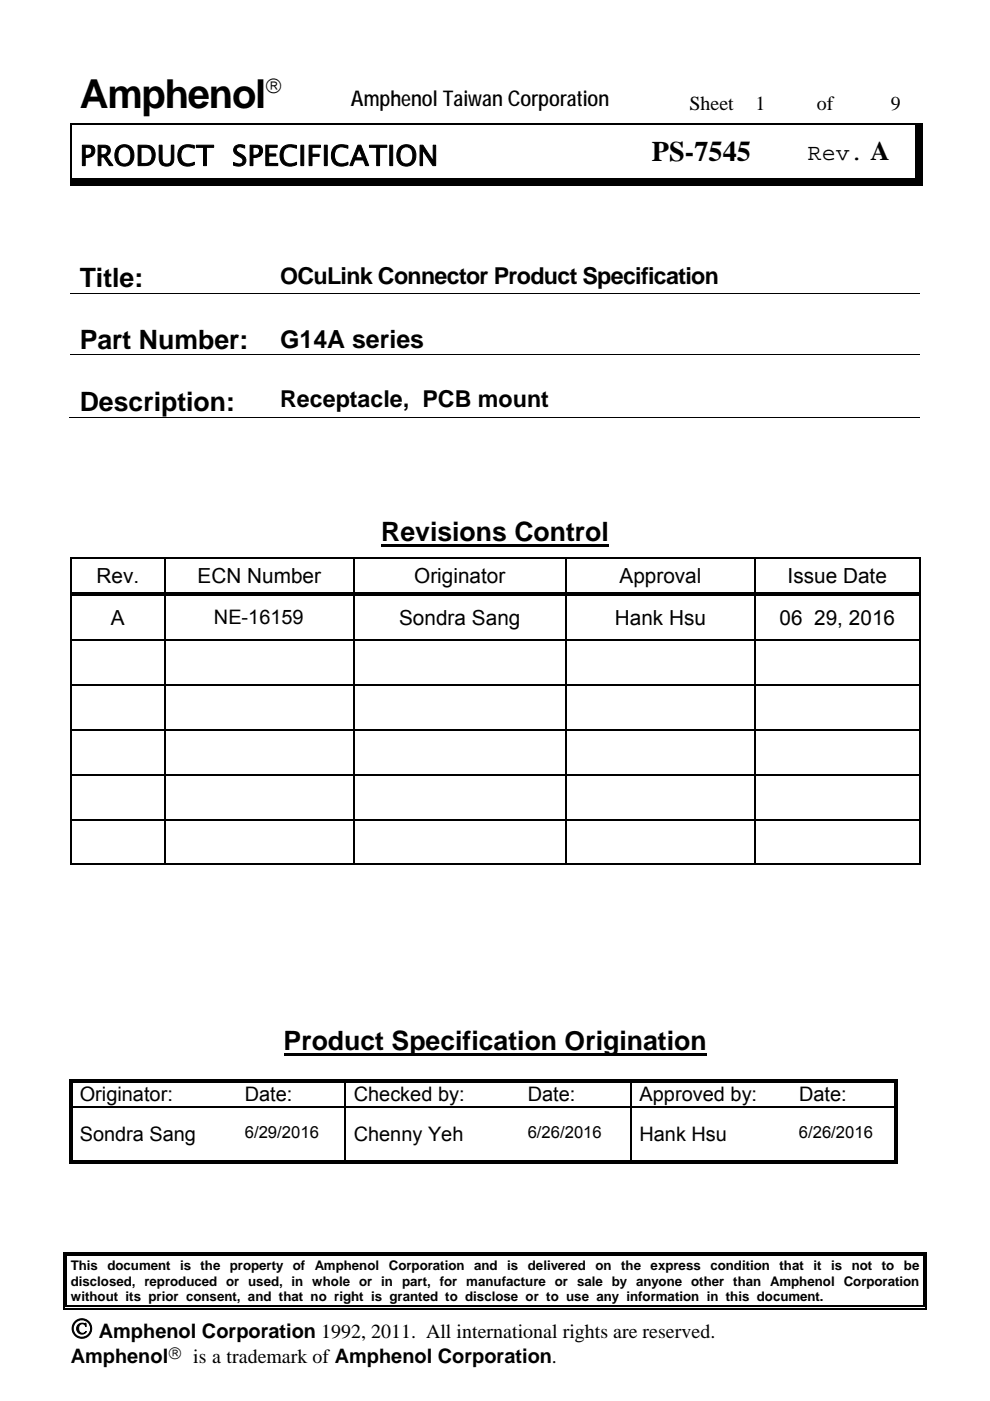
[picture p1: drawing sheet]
<svg xmlns="http://www.w3.org/2000/svg" width="210mm" height="297mm" viewBox="0 0 210 297" stroke-linecap="round" stroke-linejoin="round" font-family="sans-serif">
<defs><g id="words">
<text font-size="8.5" x="16.9" y="22.9">Amphenol</text>
<g font-size="6">
<text x="16.9" y="35.1">PRODUCT SPECIFICATION</text>
<text x="138.3" y="34.1">PS-7545</text>
<text x="15" y="283.7">©</text>
</g>
<g font-size="5.7">
<text x="184.6" y="33.8">A</text>
<text x="16.9" y="60.9">Title:</text>
<text x="16.9" y="73.9">Part Number:</text>
<text x="16.9" y="87.1">Description:</text>
<text x="80.9" y="114.8">Revisions Control</text>
<text x="60.2" y="222.7">Product Specification Origination</text>
</g>
<text font-size="5.3" x="59.4" y="73.7">G14A series</text>
<g font-size="4.9">
<text x="171.4" y="33.8">Rev.</text>
<text x="59.4" y="60.3">OCuLink Connector Product Specification</text>
<text x="59.4" y="86.4">Receptacle, PCB mount</text>
</g>
<g font-size="4.6">
<text x="56.2" y="19.8">®</text>
<text x="74.4" y="22.4">Amphenol Taiwan Corporation</text>
</g>
<g font-size="4.4">
<text x="20.5" y="123.5">Rev.</text>
<text x="41.9" y="123.5">ECN Number</text>
<text x="87.9" y="123.5">Originator</text>
<text x="131.4" y="123.5">Approval</text>
<text x="167" y="123.5">Issue Date</text>
<text x="23.5" y="132.5">A</text>
<text x="84.6" y="132.5">Sondra Sang</text>
<text x="130.4" y="132.5">Hank Hsu</text>
<text x="165.3" y="132.5">06 29, 2016</text>
</g>
<g font-size="4.2">
<text x="146.2" y="23.2">Sheet</text>
<text x="160.2" y="23.2">1</text>
<text x="173.3" y="23.2">of</text>
<text x="189" y="23.2">9</text>
<text x="45.4" y="132.4">NE-16159</text>
<text x="16.9" y="233.5">Originator:</text>
<text x="51.9" y="233.5">Date:</text>
<text x="75" y="233.5">Checked by:</text>
<text x="111.9" y="233.5">Date:</text>
<text x="135.7" y="233.5">Approved by:</text>
<text x="169.5" y="233.5">Date:</text>
<text x="16.9" y="241.9">Sondra Sang</text>
<text x="75" y="241.9">Chenny Yeh</text>
<text x="135.6" y="241.9">Hank Hsu</text>
<text x="21" y="283.7">Amphenol Corporation 1992, 2011. All international rights are reserved.</text>
<text x="15" y="289">Amphenol</text>
<text x="41" y="289">is a trademark of Amphenol Corporation.</text>
</g>
<text font-size="3.7" x="35.7" y="288.1">®</text>
<g font-size="3.5">
<text x="51.9" y="241.2">6/29/2016</text>
<text x="111.9" y="241.2">6/26/2016</text>
<text x="169.4" y="241.2">6/26/2016</text>
</g>
<g font-size="2.8">
<text x="15" y="269.2">This</text>
<text x="22.8" y="269.2">document</text>
<text x="38.2" y="269.2">is</text>
<text x="42.5" y="269.2">the</text>
<text x="48.7" y="269.2">property of</text>
<text x="66.8" y="269.2">Amphenol</text>
<text x="82.5" y="269.2">Corporation</text>
<text x="100.6" y="269.2">and</text>
<text x="107.6" y="269.2">is</text>
<text x="112" y="269.2">delivered</text>
<text x="126.3" y="269.2">on</text>
<text x="131.8" y="269.2">the</text>
<text x="138" y="269.2">express</text>
<text x="150.7" y="269.2">condition</text>
<text x="165.3" y="269.2">that</text>
<text x="172.5" y="269.2">it</text>
<text x="176.3" y="269.2">is</text>
<text x="180.7" y="269.2">not</text>
<text x="187.1" y="269.2">to</text>
<text x="191.7" y="269.2">be</text>
<text x="15" y="272.6">disclosed, reproduced or used, in whole or in part, for manufacture or sale by anyone other than Amphenol Corporation</text>
<text x="15" y="275.9">without its prior consent, and that no right is granted to disclose or to use any information in this document.</text>
</g>
</g></defs>
<g fill="#000">
<path d="M14.9 26.2h.2v.2h-.2zM14.9 37.8h117.6v1.5h-117.6zM132.3 37.8h1.6v1.5h-1.6zM133.9 37.8h31.1v1.5h-31.1zM164.8 37.8h29.4v1.5h-29.4zM194.2 26.2h1.6v.2h-1.6zM194.2 26.4h1.6v12.9h-1.6zM194.2 37.8h1.6v1.5h-1.6zM57.3 88.3h.1v.2h-.1zM14.9 118.1h.2v.3h-.2zM34.9 118.1h.2v.3h-.2zM74.9 118.1h.2v.3h-.2z"/>
<path d="M80.9 115.4h48.3v.6h-48.3zM119.9 118.1h.3v.3h-.3zM160 118.1h.3v.3h-.3zM194.9 118.1h.3v.3h-.3zM194.9 118.1h.3v.2h-.3zM14.9 125.5h.2v.8h-.2zM14.9 135.6h.2v.2h-.2zM34.9 126.3h.2zM34.9 125.5h.7v.3h-.7zM34.9 126h.7v.3h-.7zM34.9 135.6h.2v.2h-.2zM74.9 126.3h.2z"/>
<path d="M74.9 125.5h.7v.3h-.7zM74.9 126h.7v.3h-.7zM74.9 135.6h.2v.2h-.2zM119.9 126.3h.3zM119.9 125.5h.8v.3h-.8zM119.9 126h.8v.3h-.8zM119.9 135.6h.3v.2h-.3zM160 126.3h.3zM160 125.5h.8v.3h-.8zM160 126h.8v.3h-.8zM160 135.6h.3v.2h-.3zM194.9 125.5h.3v.8h-.3z"/>
<path d="M194.9 135.6h.3v.2h-.3zM14.9 145.1h.2v.3h-.2zM14.9 154.6h.2v.3h-.2zM34.9 145.1h.2v.3h-.2zM34.9 154.6h.2v.3h-.2zM74.9 145.1h.2v.3h-.2zM74.9 154.6h.2v.3h-.2zM119.9 145.1h.3v.3h-.3zM119.9 154.6h.3v.3h-.3zM160 145.1h.3v.3h-.3zM160 154.6h.3v.3h-.3zM194.9 145.1h.3v.3h-.3z"/>
<path d="M194.9 154.6h.3v.3h-.3zM14.9 164.1h.2v.3h-.2zM14.9 173.7h.2v.2h-.2zM34.9 164.1h.2v.3h-.2zM34.9 173.7h.2v.2h-.2zM74.9 164.1h.2v.3h-.2zM74.9 173.7h.2v.2h-.2zM119.9 164.1h.3v.3h-.3zM119.9 173.7h.3v.2h-.3zM160 164.1h.3v.3h-.3zM160 173.7h.3v.2h-.3zM194.9 164.1h.3v.3h-.3z"/>
<path d="M194.9 173.7h.3v.2h-.3zM194.9 183h.3v.3h-.3zM14.6 228.8h.3v.8h-.3zM14.6 228.8h.8v.2h-.8zM14.6 234.5h.3v.3h-.3zM15.1 229.3h.3v.3h-.3zM15.1 234.5h.3v.3h-.3zM50 228.8h.8v.2h-.8zM50 229.3h.8v.3h-.8zM60.2 223.3h89.7v.6h-89.7zM73 229.6h.3zM73 228.8h.8v.2h-.8z"/>
<path d="M73 229.3h.8v.3h-.8zM73 234.5h.3v.3h-.3zM110 228.8h.8v.2h-.8zM110 229.3h.8v.3h-.8zM133.6 229.6h.3zM133.6 228.8h.8v.2h-.8zM133.6 229.3h.8v.3h-.8zM133.6 234.5h.3v.3h-.3zM167.5 228.8h.8v.2h-.8zM167.5 229.3h.8v.3h-.8zM189.7 228.8h.7v.2h-.7zM189.7 229.3h.2v.3h-.2z"/>
<path d="M189.7 234.5h.2v.3h-.2zM190.2 228.8h.2v.8h-.2zM190.2 234.5h.2v.3h-.2zM14.6 246.5h.8v.3h-.8zM15.1 246h.3v.3h-.3zM49.8 246h.7v.3h-.7zM73 246h.8v.3h-.8zM109.8 246h.7v.3h-.7zM133.6 246h.8v.3h-.8zM133.6 246.5h.8v.3h-.8zM167.3 246h.7v.3h-.7zM189.7 246.5h.7v.3h-.7z"/>
<path d="M189.7 246h.2v.3h-.2zM190.2 246h.2v.8h-.2zM13.4 265.5h.2v.7h-.2zM13.4 265.5h.7v.2h-.7zM13.4 276.9h.2v.7h-.2zM13.4 277.4h.7v.2h-.7zM13.9 266h.2v.2h-.2zM13.9 276.9h.2v.2h-.2zM195.9 265.5h.7v.2h-.7zM195.9 266h.2v.2h-.2zM195.9 277.4h.7v.2h-.7zM195.9 276.9h.2v.2h-.2z"/>
<path d="M196.4 265.5h.2v.7h-.2zM196.4 276.9h.2v.7h-.2z"/>
</g>
<g fill="none" stroke="#000" stroke-width=".25">
<path d="M14.9 26.3h179.3M15 26.4v11.4M14.9 118.2h20M15 118.4v7.1M35 118.4v7.1M35.1 118.2h39.8M75 118.4v7.1M75.1 118.2h44.8M120 118.4v7.1M120.2 118.2h39.8M160.1 118.4v7.1M160.3 118.2h34.6"/>
<path d="M195 118.4v7.1M15 126.3v9.3M15 135.8v9.3M15.1 125.6h19.8M15.1 126.1h19.8M15.1 135.7h19.8M35 126.3v9.3M35 135.8v9.3M35.1 135.7h39.8M35.6 125.6h39.3M35.6 126.1h39.3M75 126.3v9.3"/>
<path d="M75 135.8v9.3M75.1 135.7h44.8M75.6 125.6h44.3M75.6 126.1h44.3M120 126.3v9.3M120 135.8v9.3M120.2 135.7h39.8M120.7 125.6h39.3M120.7 126.1h39.3M160.1 126.3v9.3M160.1 135.8v9.3M160.3 135.7h34.6"/>
<path d="M160.8 125.6h34.1M160.8 126.1h34.1M195 126.3v9.3M195 135.8v9.3M15 145.4v9.2M15 154.9v9.2M15.1 145.2h19.8M15.1 154.7h19.8M35 145.4v9.2M35 154.9v9.2M35.1 145.2h39.8M35.1 154.7h39.8"/>
<path d="M75 145.4v9.2M75 154.9v9.2M75.1 145.2h44.8M75.1 154.7h44.8M120 145.4v9.2M120 154.9v9.2M120.2 145.2h39.8M120.2 154.7h39.8M160.1 145.4v9.2M160.1 154.9v9.2M160.3 145.2h34.6M160.3 154.7h34.6"/>
<path d="M195 145.4v9.2M195 154.9v9.2M15 164.4v9.3M15 173.9v9.4M15.1 164.3h19.8M15.1 173.8h19.8M35 164.4v9.3M35 173.9v9.4M35.1 164.3h39.8M35.1 173.8h39.8M75 164.4v9.3M75 173.9v9.4"/>
<path d="M75.1 164.3h44.8M75.1 173.8h44.8M120 164.4v9.3M120 173.9v9.4M120.2 164.3h39.8M120.2 173.8h39.8M160.1 164.4v9.3M160.1 173.9v9.4M160.3 164.3h34.6M160.3 173.8h34.6M195 164.4v9.3M195 173.9v9.4"/>
<path d="M14.9 183.2h20M35.1 183.2h39.8M75.1 183.2h44.8M120.2 183.2h39.8M160.3 183.2h34.6M14.8 229.6v4.9M14.8 234.8v12M15.3 229.6v4.9M15.3 234.8v11.2M15.4 228.9h34.6M15.4 229.4h34.6M15.4 234.6h57.6"/>
<path d="M50.8 228.9h22.2M50.8 229.4h22.2M73.1 229.6v4.9M73.1 234.8v11.2M73.3 234.6h60.3M73.8 228.9h36.2M73.8 229.4h36.2M110.8 228.9h22.8M110.8 229.4h22.8M133.7 229.6v4.9M133.7 234.8v11.2M133.9 234.6h55.8"/>
<path d="M134.4 228.9h33.1M134.4 229.4h33.1M168.3 228.9h21.4M168.3 229.4h21.4M189.8 229.6v4.9M189.8 234.8v11.2M190.3 229.6v4.9M190.3 234.8v11.2M15.4 246.7h118.2M15.4 246.2h34.6M50.5 246.2h22.5M73.8 246.2h36.2"/>
<path d="M110.5 246.2h23.1M134.4 246.7h55.3M134.4 246.2h33.1M168 246.2h21.7M13.5 266.2v10.7M14 266.2v10.7M14.1 265.6h181.8M14.1 266.1h181.8M14.1 277.5h181.8M14.1 277h181.8M196 266.2v10.7M196.5 266.2v10.7"/>
</g>
<path d="M15 75.2h180M195 62.2h-180M14.8 88.4h180.2" fill="none" stroke="#000" stroke-width=".21"/>
<use href="#words"/>
</svg>
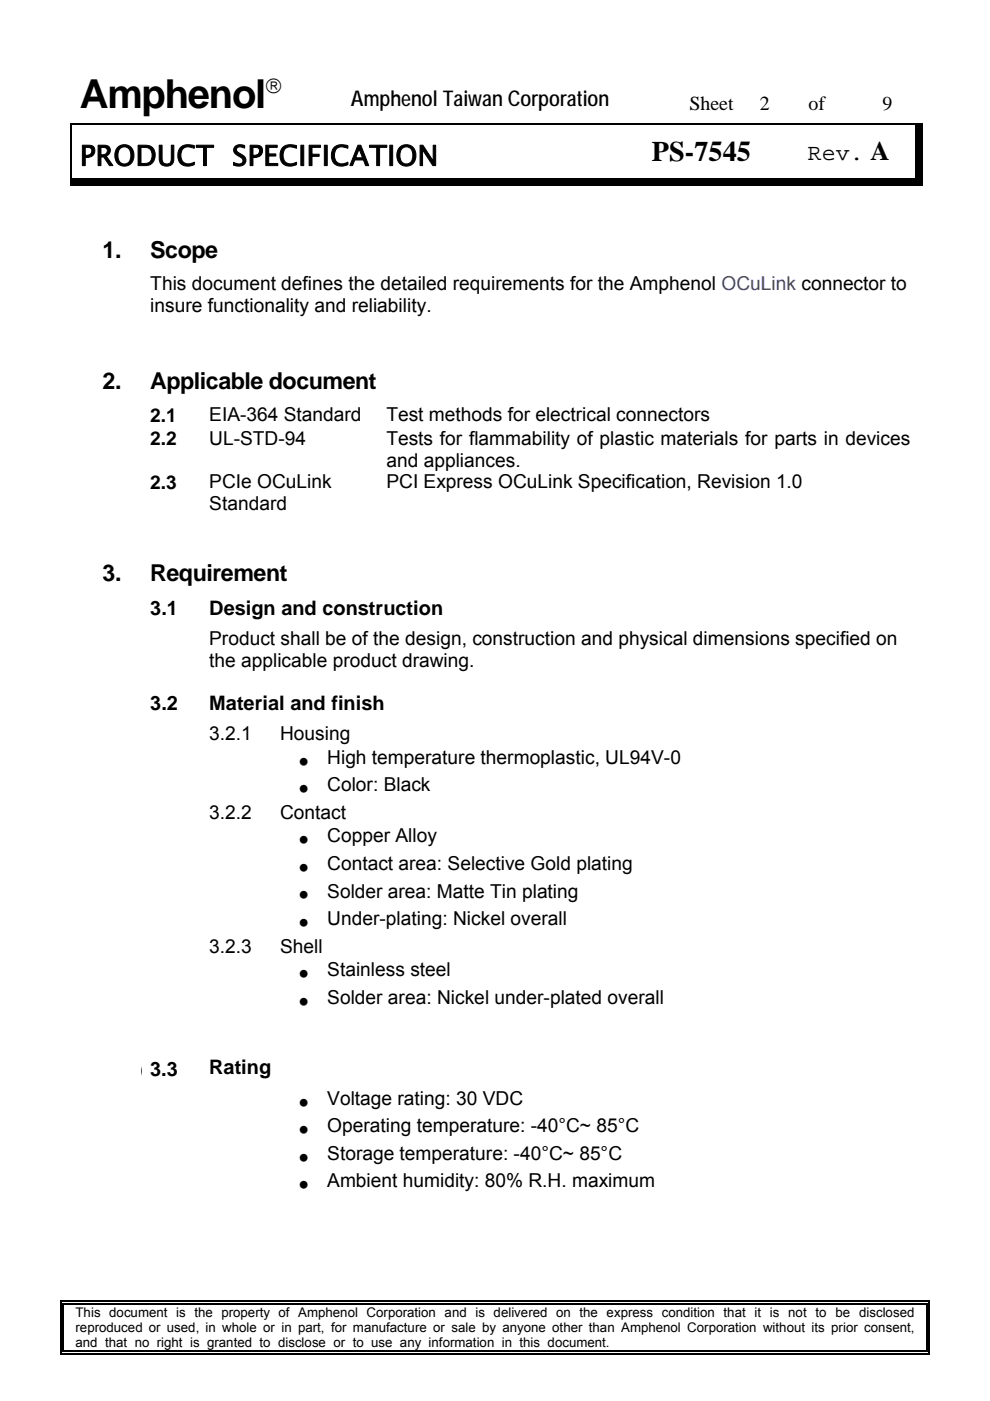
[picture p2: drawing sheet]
<svg xmlns="http://www.w3.org/2000/svg" width="210mm" height="297mm" viewBox="0 0 210 297" stroke-linecap="round" stroke-linejoin="round" font-family="sans-serif">
<defs><g id="words">
<text font-size="8.5" x="16.9" y="22.9">Amphenol</text>
<g font-size="6">
<text x="16.9" y="35.1">PRODUCT SPECIFICATION</text>
<text x="138.3" y="34.1">PS-7545</text>
</g>
<text font-size="5.7" x="184.6" y="33.8">A</text>
<g font-size="4.9">
<text x="171.4" y="33.8">Rev.</text>
<text x="21.8" y="54.6">1.</text>
<text x="31.9" y="54.6">Scope</text>
<text x="21.8" y="82.4">2.</text>
<text x="31.9" y="82.4">Applicable document</text>
<text x="21.8" y="123.1">3.</text>
<text x="31.9" y="123.1">Requirement</text>
</g>
<g font-size="4.6">
<text x="56.2" y="19.8">®</text>
<text x="74.4" y="22.4">Amphenol Taiwan Corporation</text>
<text x="63.4" y="162.8">•</text>
<text x="63.4" y="168.6">•</text>
<text x="63.4" y="179.5">•</text>
<text x="63.4" y="185.3">•</text>
<text x="63.4" y="191.1">•</text>
<text x="63.4" y="197">•</text>
<text x="63.4" y="207.8">•</text>
<text x="63.4" y="213.7">•</text>
<text x="63.4" y="235">•</text>
<text x="63.4" y="240.9">•</text>
<text x="63.4" y="246.7">•</text>
<text x="63.4" y="252.6">•</text>
</g>
<g font-size="4.2">
<text x="146.2" y="23.2">Sheet</text>
<text x="161.2" y="23.2">2</text>
<text x="171.5" y="23.2">of</text>
<text x="187.2" y="23.2">9</text>
<text x="31.9" y="130.3">3.1</text>
<text x="44.4" y="130.3">Design and construction</text>
<text x="31.9" y="150.5">3.2</text>
<text x="44.4" y="150.5">Material and finish</text>
<text x="44.4" y="227.7">Rating</text>
</g>
<g font-size="4.1">
<text x="31.9" y="61.6">This document defines the detailed requirements for the Amphenol OCuLink connector to</text>
<text x="31.9" y="66.2">insure functionality and reliability.</text>
<text x="31.9" y="89.5">2.1</text>
<text x="44.4" y="89.3">EIA-364 Standard</text>
<text x="81.9" y="89.3">Test methods for electrical connectors</text>
<text x="31.9" y="94.4">2.2</text>
<text x="44.4" y="94.3">UL-STD-94</text>
<text x="81.9" y="94.3">Tests for flammability of plastic materials for parts in devices</text>
<text x="82" y="98.9">and appliances.</text>
<text x="31.9" y="103.7">2.3</text>
<text x="44.4" y="103.6">PCIe OCuLink</text>
<text x="82" y="103.6">PCI Express OCuLink Specification, Revision 1.0</text>
<text x="44.4" y="108.2">Standard</text>
<text x="44.4" y="136.8">Product shall be of the design, construction and physical dimensions specified on</text>
<text x="44.4" y="141.4">the applicable product drawing.</text>
<text x="44.4" y="156.9">3.2.1</text>
<text x="59.4" y="156.9">Housing</text>
<text x="69.4" y="161.9">High temperature thermoplastic, UL94V-0</text>
<text x="69.4" y="167.8">Color: Black</text>
<text x="44.4" y="173.6">3.2.2</text>
<text x="59.4" y="173.6">Contact</text>
<text x="69.4" y="178.6">Copper Alloy</text>
<text x="69.4" y="184.4">Contact area: Selective Gold plating</text>
<text x="69.4" y="190.3">Solder area: Matte Tin plating</text>
<text x="69.4" y="196.1">Under-plating: Nickel overall</text>
<text x="44.4" y="202">3.2.3</text>
<text x="59.4" y="202">Shell</text>
<text x="69.4" y="207">Stainless steel</text>
<text x="69.4" y="212.8">Solder area: Nickel under-plated overall</text>
<text x="28.9" y="228.1">) 3.3</text>
<text x="69.4" y="234.2">Voltage rating: 30 VDC</text>
<text x="69.4" y="240">Operating temperature: -40°C~ 85°C</text>
<text x="69.4" y="245.9">Storage temperature: -40°C~ 85°C</text>
<text x="69.4" y="251.7">Ambient humidity: 80% R.H. maximum</text>
</g>
<g font-size="2.8">
<text x="16" y="279.2">This document is the property of Amphenol Corporation and is delivered on the express condition that it is not to be disclosed</text>
<text x="16" y="282.4">reproduced or used, in whole or in part, for manufacture or sale by anyone other than Amphenol Corporation without its prior consent,</text>
<text x="16" y="285.7">and that no right is granted to disclose or to use any information in this document.</text>
</g>
</g></defs>
<g fill="#000">
<path d="M14.9 26.2h.2v.2h-.2zM14.9 37.8h117.6v1.5h-117.6zM132.3 37.8h1.6v1.5h-1.6zM133.9 37.8h31.1v1.5h-31.1zM164.8 37.8h29.4v1.5h-29.4zM194.2 26.2h1.6v.2h-1.6zM194.2 26.4h1.6v12.9h-1.6zM194.2 37.8h1.6v1.5h-1.6zM12.7 275.8h.3v.8h-.3zM12.7 275.8h.8v.2h-.8zM13.2 276.3h.3v.3h-.3zM13.2 276.3h.3v.2h-.3z"/>
<path d="M13.5 275.8h.7v.2h-.7zM13.5 276.3h.7v.2h-.7zM105 275.8h.8v.2h-.8zM105 276.3h.8v.2h-.8zM196.5 275.8h.8v.2h-.8zM196.5 276.3h.3v.3h-.3zM196.5 276.3h.3v.2h-.3zM197 275.8h.3v.8h-.3zM12.7 286.9h.8v.2h-.8zM13.2 286.3h.3v.3h-.3zM196.5 286.9h.8v.2h-.8zM196.5 286.3h.3v.3h-.3z"/>
<path d="M197 286.3h.3v.8h-.3z"/>
</g>
<path d="M14.9 26.3h179.3M15 26.4v11.4M12.8 276.6v10.5M13.4 276.6v9.7M14.2 275.9h90.8M14.2 276.4h90.8M105.8 275.9h90.7M105.8 276.4h90.7M196.6 276.6v9.7M197.1 276.6v9.7M13.5 287h183M13.5 286.5h183" fill="none" stroke="#000" stroke-width=".25"/>
<use href="#words"/>
</svg>
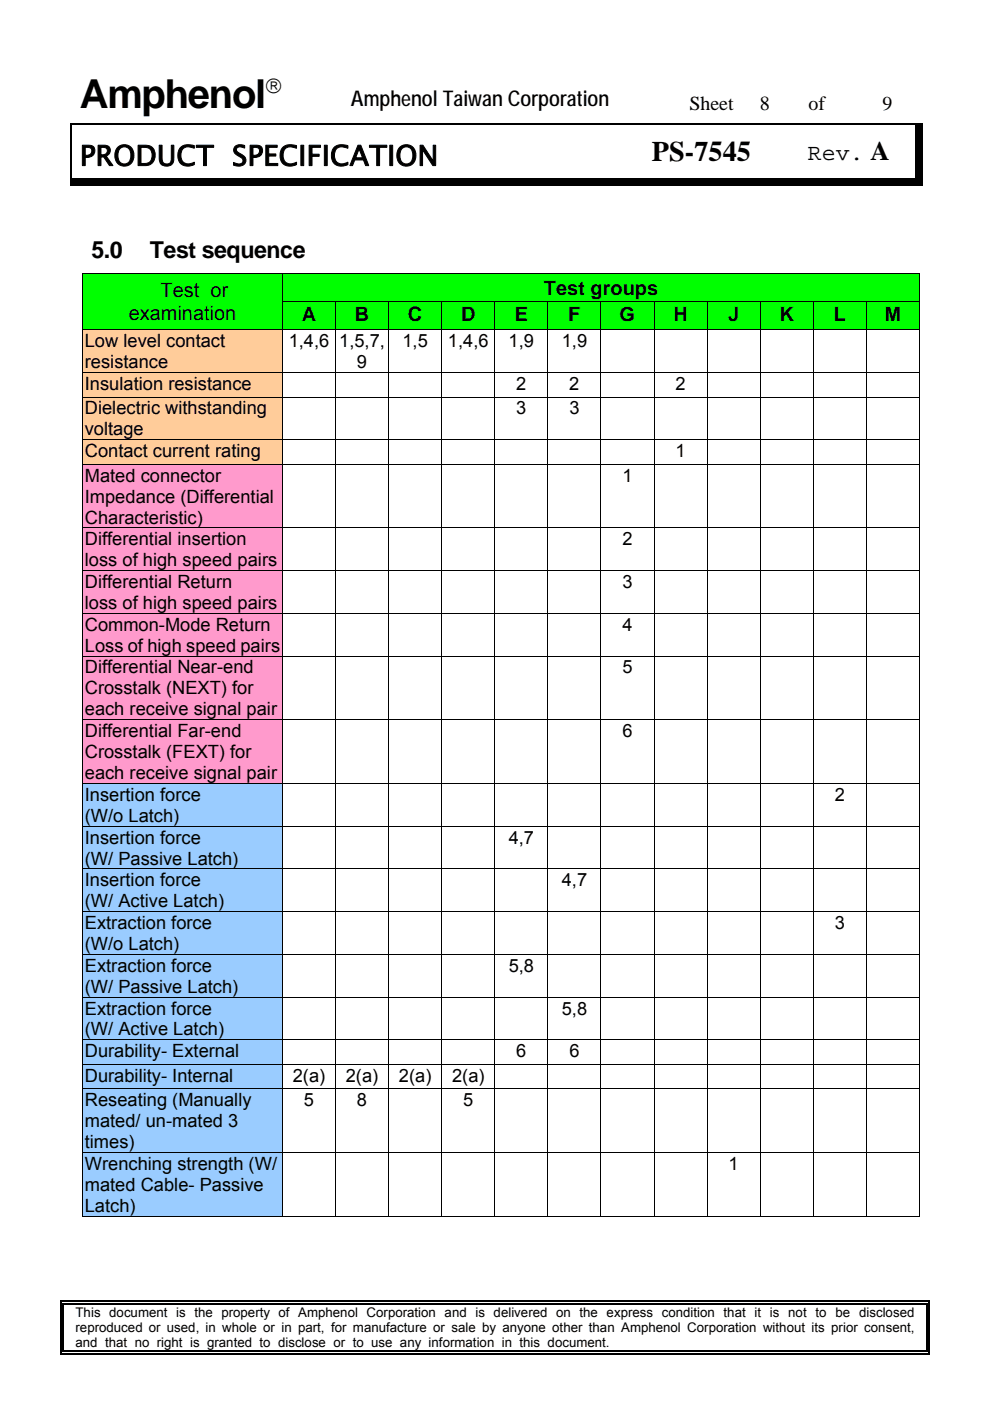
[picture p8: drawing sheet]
<svg xmlns="http://www.w3.org/2000/svg" width="210mm" height="297mm" viewBox="0 0 210 297" stroke-linecap="round" stroke-linejoin="round" font-family="sans-serif">
<defs><g id="words">
<text font-size="8.5" x="16.9" y="22.9">Amphenol</text>
<g font-size="6">
<text x="16.9" y="35.1">PRODUCT SPECIFICATION</text>
<text x="138.3" y="34.1">PS-7545</text>
</g>
<text font-size="5.7" x="184.6" y="33.8">A</text>
<g font-size="4.9">
<text x="171.4" y="33.8">Rev.</text>
<text x="19.4" y="54.7">5.0</text>
<text x="31.8" y="54.7">Test sequence</text>
</g>
<g font-size="4.6">
<text x="56.2" y="19.8">®</text>
<text x="74.4" y="22.4">Amphenol Taiwan Corporation</text>
</g>
<g font-size="4.2">
<text x="146.2" y="23.2">Sheet</text>
<text x="161.2" y="23.2">8</text>
<text x="171.5" y="23.2">of</text>
<text x="187.2" y="23.2">9</text>
<text x="34.1" y="63">Test or</text>
<text x="115.4" y="62.5">Test groups</text>
<text x="27.3" y="67.9">examination</text>
<text x="64" y="68.1">A</text>
<text x="75.3" y="68.1">B</text>
<text x="86.5" y="68.1">C</text>
<text x="97.8" y="68.1">D</text>
<text x="109.2" y="68.1">E</text>
<text x="120.5" y="68.1">F</text>
<text x="131.4" y="68.1">G</text>
<text x="142.8" y="68.1">H</text>
<text x="154.5" y="68.1">J</text>
<text x="165.3" y="68.1">K</text>
<text x="176.8" y="68.1">L</text>
<text x="187.6" y="68.1">M</text>
</g>
<g font-size="3.9">
<text x="18" y="73.6">Low level contact</text>
<text x="61.2" y="73.6">1,4,6 1,5,7,</text>
<text x="85.4" y="73.6">1,5</text>
<text x="95" y="73.6">1,4,6</text>
<text x="107.9" y="73.6">1,9</text>
<text x="119.1" y="73.6">1,9</text>
<text x="18" y="78.1">resistance</text>
<text x="18" y="82.7">Insulation resistance</text>
<text x="75.7" y="78.1">9</text>
<text x="109.5" y="82.7">2</text>
<text x="120.7" y="82.7">2</text>
<text x="143.3" y="82.7">2</text>
<text x="18" y="87.9">Dielectric withstanding</text>
<text x="109.5" y="87.9">3</text>
<text x="120.8" y="87.9">3</text>
<text x="18" y="92.3">voltage</text>
<text x="18" y="96.9">Contact current rating</text>
<text x="143.3" y="96.9">1</text>
<text x="18" y="102.1">Mated connector</text>
<text x="18" y="106.6">Impedance (Differential</text>
<text x="132" y="102.1">1</text>
<text x="18" y="111">Characteristic)</text>
<text x="18" y="115.6">Differential insertion</text>
<text x="132" y="115.6">2</text>
<text x="18" y="120.1">loss of high speed pairs</text>
<text x="18" y="124.7">Differential Return</text>
<text x="132" y="124.7">3</text>
<text x="18" y="129.1">loss of high speed pairs</text>
<text x="18" y="133.7">Common-Mode Return</text>
<text x="132" y="133.7">4</text>
<text x="18" y="138.2">Loss of high speed pairs</text>
<text x="18" y="142.8">Differential Near-end</text>
<text x="132" y="142.8">5</text>
<text x="18" y="147.2">Crosstalk (NEXT) for</text>
<text x="18" y="151.7">each receive signal pair</text>
<text x="18" y="156.3">Differential Far-end</text>
<text x="18" y="160.7">Crosstalk (FEXT) for</text>
<text x="132" y="156.3">6</text>
<text x="18" y="165.2">each receive signal pair</text>
<text x="18" y="169.8">Insertion force</text>
<text x="177" y="169.8">2</text>
<text x="18" y="174.2">(W/o Latch)</text>
<text x="18" y="178.9">Insertion force</text>
<text x="107.9" y="178.9">4,7</text>
<text x="18" y="183.3">(W/ Passive Latch)</text>
<text x="18" y="187.9">Insertion force</text>
<text x="119.2" y="187.9">4,7</text>
<text x="18" y="192.4">(W/ Active Latch)</text>
<text x="18" y="197">Extraction force</text>
<text x="177" y="197">3</text>
<text x="18" y="201.4">(W/o Latch)</text>
<text x="18" y="206">Extraction force</text>
<text x="107.9" y="206">5,8</text>
<text x="18" y="210.5">(W/ Passive Latch)</text>
<text x="18" y="215.1">Extraction force</text>
<text x="119.2" y="215.1">5,8</text>
<text x="18" y="219.5">(W/ Active Latch)</text>
<text x="18" y="224.2">Durability- External</text>
<text x="109.5" y="224.2">6</text>
<text x="120.8" y="224.2">6</text>
<text x="18" y="229.3">Durability- Internal</text>
<text x="62.1" y="229.3">2(a)</text>
<text x="73.3" y="229.3">2(a)</text>
<text x="84.6" y="229.3">2(a)</text>
<text x="95.9" y="229.3">2(a)</text>
<text x="18" y="234.5">Reseating (Manually</text>
<text x="18" y="239">mated/ un-mated 3</text>
<text x="64.5" y="234.5">5</text>
<text x="75.7" y="234.5">8</text>
<text x="98.3" y="234.5">5</text>
<text x="18" y="243.4">times)</text>
<text x="18" y="248">Wrenching strength (W/</text>
<text x="154.5" y="248">1</text>
<text x="18" y="252.5">mated Cable- Passive</text>
<text x="18" y="256.9">Latch)</text>
</g>
<g font-size="2.8">
<text x="16" y="279.2">This document is the property of Amphenol Corporation and is delivered on the express condition that it is not to be disclosed</text>
<text x="16" y="282.4">reproduced or used, in whole or in part, for manufacture or sale by anyone other than Amphenol Corporation without its prior consent,</text>
<text x="16" y="285.7">and that no right is granted to disclose or to use any information in this document.</text>
</g>
</g></defs>
<g fill="#000">
<path d="M14.9 26.2h.2v.2h-.2zM14.9 37.8h117.6v1.5h-117.6zM132.3 37.8h1.6v1.5h-1.6zM133.9 37.8h31.1v1.5h-31.1zM164.8 37.8h29.4v1.5h-29.4zM194.2 26.2h1.6v.2h-1.6zM194.2 26.4h1.6v12.9h-1.6zM194.2 37.8h1.6v1.5h-1.6zM12.7 275.8h.3v.8h-.3zM12.7 275.8h.8v.2h-.8zM13.2 276.3h.3v.3h-.3zM13.2 276.3h.3v.2h-.3z"/>
<path d="M13.5 275.8h.7v.2h-.7zM13.5 276.3h.7v.2h-.7zM105 275.8h.8v.2h-.8zM105 276.3h.8v.2h-.8zM196.5 275.8h.8v.2h-.8zM196.5 276.3h.3v.3h-.3zM196.5 276.3h.3v.2h-.3zM197 275.8h.3v.8h-.3zM12.7 286.9h.8v.2h-.8zM13.2 286.3h.3v.3h-.3zM196.5 286.9h.8v.2h-.8zM196.5 286.3h.3v.3h-.3z"/>
<path d="M197 286.3h.3v.8h-.3z"/>
</g>
<path d="M14.9 26.3h179.3M15 26.4v11.4M12.8 276.6v10.5M13.4 276.6v9.7M14.2 275.9h90.8M14.2 276.4h90.8M105.8 275.9h90.7M105.8 276.4h90.7M196.6 276.6v9.7M197.1 276.6v9.7M13.5 287h183M13.5 286.5h183" fill="none" stroke="#000" stroke-width=".25"/>
<g fill="#0f0">
<path d="M17.6 58h42.2v11.8h-42.2z"/>
<path d="M18 59.1h41.4v4.8h-41.4z"/>
<path d="M18 63.9h41.4v4.9h-41.4z"/>
<path d="M59.9 58h135v5.9h-135z"/>
<path d="M60.4 58.5h134.1v4.9h-134.1z"/>
</g>
<path d="M17.4 57.9h.2v.1h-.2zM194.9 57.9h.2v.1h-.2z" fill="#000"/>
<path d="M17.5 58v5.9M59.9 58v5.9M194.9 58h-177.5M195 58v5.9" fill="none" stroke="#000" stroke-width=".21"/>
<g fill="#0f0">
<path d="M59.9 64h11.2v5.8h-11.2z"/>
<path d="M60.4 64h10.3v5h-10.3z"/>
<path d="M71.2 64h11.2v5.8h-11.2z"/>
<path d="M71.7 64h10.2v5h-10.2z"/>
<path d="M82.4 64h11.2v5.8h-11.2z"/>
<path d="M82.9 64h10.3v5h-10.3z"/>
<path d="M93.7 64h11.2v5.8h-11.2z"/>
<path d="M94.2 64h10.3v5h-10.3z"/>
<path d="M105 64h11.1v5.8h-11.1z"/>
<path d="M105.5 64h10.2v5h-10.2z"/>
<path d="M116.2 64h11.2v5.8h-11.2z"/>
<path d="M116.7 64h10.3v5h-10.3z"/>
<path d="M127.5 64h11.1v5.8h-11.1z"/>
<path d="M128 64h10.2v5h-10.2z"/>
<path d="M138.7 64h11.2v5.8h-11.2z"/>
<path d="M139.2 64h10.3v5h-10.3z"/>
<path d="M150 64h11.2v5.8h-11.2z"/>
<path d="M150.5 64h10.3v5h-10.3z"/>
<path d="M161.3 64h11.1v5.8h-11.1z"/>
<path d="M161.7 64h10.3v5h-10.3z"/>
<path d="M172.6 64h11.1v5.8h-11.1z"/>
<path d="M173 64h10.3v5h-10.3z"/>
<path d="M183.9 64h11v5.8h-11z"/>
<path d="M184.3 64h10.2v5h-10.2z"/>
</g>
<path d="M17.4 63.9h.2v.1h-.2z" fill="#000"/>
<g fill="none" stroke="#000" stroke-width=".21">
<path d="M17.5 64v5.8M59.9 63.9h135.2M59.9 64v5.8M71.2 64v5.8M82.4 64v5.8M93.7 64v5.8M105 64v5.8M116.2 64v5.8M127.5 64v5.8M138.7 64v5.8M150 64v5.8M161.2 64v5.8"/>
<path d="M172.5 64v5.8M183.8 64v5.8M195 64v5.8"/>
</g>
<g fill="#ffcc9a">
<path d="M17.6 70h42.2v8.9h-42.2z"/>
<path d="M18 70h41.4v4.5h-41.4z"/>
<path d="M18 74.5h41.4v4.4h-41.4z"/>
</g>
<g fill="none" stroke="#000" stroke-width=".21">
<path d="M17.4 69.9h177.7M17.5 70v8.9M59.9 70v8.9M71.2 70v8.9M82.4 70v8.9M93.7 70v8.9M105 70v8.9M116.2 70v8.9M127.5 70v8.9M138.7 70v8.9M150 70v8.9M161.2 70v8.9"/>
<path d="M172.5 70v8.9M183.8 70v8.9M195 70v8.9"/>
</g>
<g fill="#ffcc9a">
<path d="M17.6 79.1h42.2v5h-42.2z"/>
<path d="M18 79.1h41.4v4.4h-41.4z"/>
</g>
<g fill="none" stroke="#000" stroke-width=".21">
<path d="M17.4 79h177.7M17.5 79.1v5M59.9 79.1v5M71.2 79.1v5M82.4 79.1v5M93.7 79.1v5M105 79.1v5M116.2 79.1v5M127.5 79.1v5M138.7 79.1v5M150 79.1v5M161.2 79.1v5"/>
<path d="M172.5 79.1v5M183.8 79.1v5M195 79.1v5"/>
</g>
<g fill="#ffcc9a">
<path d="M17.6 84.3h42.2v8.9h-42.2z"/>
<path d="M18 84.3h41.4v4.4h-41.4z"/>
<path d="M18 88.7h41.4v4.5h-41.4z"/>
</g>
<g fill="none" stroke="#000" stroke-width=".21">
<path d="M17.4 84.2h177.7M17.5 84.3v8.9M59.9 84.3v8.9M71.2 84.3v8.9M82.4 84.3v8.9M93.7 84.3v8.9M105 84.3v8.9M116.2 84.3v8.9M127.5 84.3v8.9M138.7 84.3v8.9M150 84.3v8.9M161.2 84.3v8.9"/>
<path d="M172.5 84.3v8.9M183.8 84.3v8.9M195 84.3v8.9"/>
</g>
<g fill="#ffcc9a">
<path d="M17.6 93.3h42.2v5h-42.2z"/>
<path d="M18 93.3h41.4v4.5h-41.4z"/>
</g>
<g fill="none" stroke="#000" stroke-width=".21">
<path d="M17.4 93.2h177.7M17.5 93.3v5M59.9 93.3v5M71.2 93.3v5M82.4 93.3v5M93.7 93.3v5M105 93.3v5M116.2 93.3v5M127.5 93.3v5M138.7 93.3v5M150 93.3v5M161.2 93.3v5"/>
<path d="M172.5 93.3v5M183.8 93.3v5M195 93.3v5"/>
</g>
<g fill="#ff9acc">
<path d="M17.6 98.5h42.2v13.3h-42.2z"/>
<path d="M18 98.5h41.4v4.5h-41.4z"/>
<path d="M18 103h41.4v4.4h-41.4z"/>
<path d="M18 107.4h41.4v4.4h-41.4z"/>
</g>
<g fill="none" stroke="#000" stroke-width=".21">
<path d="M17.4 98.4h177.7M17.5 98.5v13.3M59.9 98.5v13.3M71.2 98.5v13.3M82.4 98.5v13.3M93.7 98.5v13.3M105 98.5v13.3M116.2 98.5v13.3M127.5 98.5v13.3M138.7 98.5v13.3M150 98.5v13.3M161.2 98.5v13.3"/>
<path d="M172.5 98.5v13.3M183.8 98.5v13.3M195 98.5v13.3"/>
</g>
<g fill="#ff9acc">
<path d="M17.6 112h42.2v8.9h-42.2z"/>
<path d="M18 112h41.4v4.5h-41.4z"/>
<path d="M18 116.5h41.4v4.4h-41.4z"/>
</g>
<g fill="none" stroke="#000" stroke-width=".21">
<path d="M17.4 111.9h177.7M17.5 112v8.9M59.9 112v8.9M71.2 112v8.9M82.4 112v8.9M93.7 112v8.9M105 112v8.9M116.2 112v8.9M127.5 112v8.9M138.7 112v8.9M150 112v8.9M161.2 112v8.9"/>
<path d="M172.5 112v8.9M183.8 112v8.9M195 112v8.9"/>
</g>
<g fill="#ff9acc">
<path d="M17.6 121.1h42.2v8.9h-42.2z"/>
<path d="M18 121.1h41.4v4.4h-41.4z"/>
<path d="M18 125.5h41.4v4.5h-41.4z"/>
</g>
<g fill="none" stroke="#000" stroke-width=".21">
<path d="M17.4 121h177.7M17.5 121.1v8.9M59.9 121.1v8.9M71.2 121.1v8.9M82.4 121.1v8.9M93.7 121.1v8.9M105 121.1v8.9M116.2 121.1v8.9M127.5 121.1v8.9M138.7 121.1v8.9M150 121.1v8.9M161.2 121.1v8.9"/>
<path d="M172.5 121.1v8.9M183.8 121.1v8.9M195 121.1v8.9"/>
</g>
<g fill="#ff9acc">
<path d="M17.6 130.1h42.2v8.9h-42.2z"/>
<path d="M18 130.1h41.4v4.5h-41.4z"/>
<path d="M18 134.6h41.4v4.4h-41.4z"/>
</g>
<g fill="none" stroke="#000" stroke-width=".21">
<path d="M17.4 130h177.7M17.5 130.1v8.9M59.9 130.1v8.9M71.2 130.1v8.9M82.4 130.1v8.9M93.7 130.1v8.9M105 130.1v8.9M116.2 130.1v8.9M127.5 130.1v8.9M138.7 130.1v8.9M150 130.1v8.9M161.2 130.1v8.9"/>
<path d="M172.5 130.1v8.9M183.8 130.1v8.9M195 130.1v8.9"/>
</g>
<g fill="#ff9acc">
<path d="M17.6 139.2h42.2v13.3h-42.2z"/>
<path d="M18 139.2h41.4v4.4h-41.4z"/>
<path d="M18 143.6h41.4v4.5h-41.4z"/>
<path d="M18 148.1h41.4v4.4h-41.4z"/>
</g>
<g fill="none" stroke="#000" stroke-width=".21">
<path d="M17.4 139.1h177.7M17.5 139.2v13.3M59.9 139.2v13.3M71.2 139.2v13.3M82.4 139.2v13.3M93.7 139.2v13.3M105 139.2v13.3M116.2 139.2v13.3M127.5 139.2v13.3M138.7 139.2v13.3M150 139.2v13.3M161.2 139.2v13.3"/>
<path d="M172.5 139.2v13.3M183.8 139.2v13.3M195 139.2v13.3"/>
</g>
<g fill="#ff9acc">
<path d="M17.6 152.7h42.2v13.3h-42.2z"/>
<path d="M18 152.7h41.4v4.4h-41.4z"/>
<path d="M18 157.1h41.4v4.5h-41.4z"/>
<path d="M18 161.6h41.4v4.4h-41.4z"/>
</g>
<g fill="none" stroke="#000" stroke-width=".21">
<path d="M17.4 152.6h177.7M17.5 152.7v13.3M59.9 152.7v13.3M71.2 152.7v13.3M82.4 152.7v13.3M93.7 152.7v13.3M105 152.7v13.3M116.2 152.7v13.3M127.5 152.7v13.3M138.7 152.7v13.3M150 152.7v13.3M161.2 152.7v13.3"/>
<path d="M172.5 152.7v13.3M183.8 152.7v13.3M195 152.7v13.3"/>
</g>
<g fill="#9accff">
<path d="M17.6 166.2h42.2v8.9h-42.2z"/>
<path d="M18 166.2h41.4v4.4h-41.4z"/>
<path d="M18 170.6h41.4v4.5h-41.4z"/>
</g>
<g fill="none" stroke="#000" stroke-width=".21">
<path d="M17.4 166.1h177.7M17.5 166.2v8.9M59.9 166.2v8.9M71.2 166.2v8.9M82.4 166.2v8.9M93.7 166.2v8.9M105 166.2v8.9M116.2 166.2v8.9M127.5 166.2v8.9M138.7 166.2v8.9M150 166.2v8.9M161.2 166.2v8.9"/>
<path d="M172.5 166.2v8.9M183.8 166.2v8.9M195 166.2v8.9"/>
</g>
<g fill="#9accff">
<path d="M17.6 175.3h42.2v8.8h-42.2z"/>
<path d="M18 175.3h41.4v4.4h-41.4z"/>
<path d="M18 179.7h41.4v4.4h-41.4z"/>
</g>
<g fill="none" stroke="#000" stroke-width=".21">
<path d="M17.4 175.2h177.7M17.5 175.3v8.8M59.9 175.3v8.8M71.2 175.3v8.8M82.4 175.3v8.8M93.7 175.3v8.8M105 175.3v8.8M116.2 175.3v8.8M127.5 175.3v8.8M138.7 175.3v8.8M150 175.3v8.8M161.2 175.3v8.8"/>
<path d="M172.5 175.3v8.8M183.8 175.3v8.8M195 175.3v8.8"/>
</g>
<g fill="#9accff">
<path d="M17.6 184.3h42.2v8.9h-42.2z"/>
<path d="M18 184.3h41.4v4.5h-41.4z"/>
<path d="M18 188.8h41.4v4.4h-41.4z"/>
</g>
<g fill="none" stroke="#000" stroke-width=".21">
<path d="M17.4 184.2h177.7M17.5 184.3v8.9M59.9 184.3v8.9M71.2 184.3v8.9M82.4 184.3v8.9M93.7 184.3v8.9M105 184.3v8.9M116.2 184.3v8.9M127.5 184.3v8.9M138.7 184.3v8.9M150 184.3v8.9M161.2 184.3v8.9"/>
<path d="M172.5 184.3v8.9M183.8 184.3v8.9M195 184.3v8.9"/>
</g>
<g fill="#9accff">
<path d="M17.6 193.4h42.2v8.9h-42.2z"/>
<path d="M18 193.4h41.4v4.4h-41.4z"/>
<path d="M18 197.8h41.4v4.5h-41.4z"/>
</g>
<g fill="none" stroke="#000" stroke-width=".21">
<path d="M17.4 193.3h177.7M17.5 193.4v8.9M59.9 193.4v8.9M71.2 193.4v8.9M82.4 193.4v8.9M93.7 193.4v8.9M105 193.4v8.9M116.2 193.4v8.9M127.5 193.4v8.9M138.7 193.4v8.9M150 193.4v8.9M161.2 193.4v8.9"/>
<path d="M172.5 193.4v8.9M183.8 193.4v8.9M195 193.4v8.9"/>
</g>
<g fill="#9accff">
<path d="M17.6 202.4h42.2v8.9h-42.2z"/>
<path d="M18 202.4h41.4v4.5h-41.4z"/>
<path d="M18 206.9h41.4v4.4h-41.4z"/>
</g>
<g fill="none" stroke="#000" stroke-width=".21">
<path d="M17.4 202.4h177.7M17.5 202.4v8.9M59.9 202.4v8.9M71.2 202.4v8.9M82.4 202.4v8.9M93.7 202.4v8.9M105 202.4v8.9M116.2 202.4v8.9M127.5 202.4v8.9M138.7 202.4v8.9M150 202.4v8.9M161.2 202.4v8.9"/>
<path d="M172.5 202.4v8.9M183.8 202.4v8.9M195 202.4v8.9"/>
</g>
<g fill="#9accff">
<path d="M17.6 211.5h42.2v8.9h-42.2z"/>
<path d="M18 211.5h41.4v4.4h-41.4z"/>
<path d="M18 215.9h41.4v4.5h-41.4z"/>
</g>
<g fill="none" stroke="#000" stroke-width=".21">
<path d="M17.4 211.4h177.7M17.5 211.5v8.9M59.9 211.5v8.9M71.2 211.5v8.9M82.4 211.5v8.9M93.7 211.5v8.9M105 211.5v8.9M116.2 211.5v8.9M127.5 211.5v8.9M138.7 211.5v8.9M150 211.5v8.9M161.2 211.5v8.9"/>
<path d="M172.5 211.5v8.9M183.8 211.5v8.9M195 211.5v8.9"/>
</g>
<g fill="#9accff">
<path d="M17.6 220.6h42.2v5h-42.2z"/>
<path d="M18 220.6h41.4v4.4h-41.4z"/>
</g>
<g fill="none" stroke="#000" stroke-width=".21">
<path d="M17.4 220.5h177.7M17.5 220.6v5M59.9 220.6v5M71.2 220.6v5M82.4 220.6v5M93.7 220.6v5M105 220.6v5M116.2 220.6v5M127.5 220.6v5M138.7 220.6v5M150 220.6v5M161.2 220.6v5"/>
<path d="M172.5 220.6v5M183.8 220.6v5M195 220.6v5"/>
</g>
<g fill="#9accff">
<path d="M17.6 225.7h42.2v5.1h-42.2z"/>
<path d="M18 225.7h41.4v4.5h-41.4z"/>
</g>
<g fill="none" stroke="#000" stroke-width=".21">
<path d="M17.4 225.7h177.7M17.5 225.7v5.1M59.9 225.7v5.1M71.2 225.7v5.1M82.4 225.7v5.1M93.7 225.7v5.1M105 225.7v5.1M116.2 225.7v5.1M127.5 225.7v5.1M138.7 225.7v5.1M150 225.7v5.1M161.2 225.7v5.1"/>
<path d="M172.5 225.7v5.1M183.8 225.7v5.1M195 225.7v5.1"/>
</g>
<g fill="#9accff">
<path d="M17.6 230.9h42.2v13.4h-42.2z"/>
<path d="M18 230.9h41.4v4.5h-41.4z"/>
<path d="M18 235.4h41.4v4.4h-41.4z"/>
<path d="M18 239.8h41.4v4.5h-41.4z"/>
</g>
<g fill="none" stroke="#000" stroke-width=".21">
<path d="M17.4 230.8h177.7M17.5 230.9v13.4M59.9 230.9v13.4M71.2 230.9v13.4M82.4 230.9v13.4M93.7 230.9v13.4M105 230.9v13.4M116.2 230.9v13.4M127.5 230.9v13.4M138.7 230.9v13.4M150 230.9v13.4M161.2 230.9v13.4"/>
<path d="M172.5 230.9v13.4M183.8 230.9v13.4M195 230.9v13.4"/>
</g>
<g fill="#9accff">
<path d="M17.6 244.4h42.2v13.4h-42.2z"/>
<path d="M18 244.4h41.4v4.5h-41.4z"/>
<path d="M18 248.9h41.4v4.4h-41.4z"/>
<path d="M18 253.3h41.4v4.5h-41.4z"/>
</g>
<g fill="none" stroke="#000" stroke-width=".21">
<path d="M17.4 244.3h177.7M17.4 257.9h42.5M17.5 244.4v13.5M59.9 244.4v13.5M60 257.9h11.1M71.2 244.4v13.5M71.3 257.9h11.1M82.4 244.4v13.5M82.5 257.9h11.1M93.7 244.4v13.5M93.8 257.9h11.1M105 244.4v13.5"/>
<path d="M105.1 257.9h11M116.2 244.4v13.5M116.3 257.9h11.1M127.5 244.4v13.5M127.6 257.9h11M138.7 244.4v13.5M138.8 257.9h11.1M150 244.4v13.5M150.1 257.9h11.1M161.2 244.4v13.5M161.3 257.9h11.1M172.5 244.4v13.5"/>
<path d="M172.6 257.9h11.1M183.8 244.4v13.5M183.9 257.9h11M195 244.4v13.5"/>
</g>
<path d="M194.9 257.8h.2v.1h-.2z" fill="#000"/>
<use href="#words"/>
</svg>
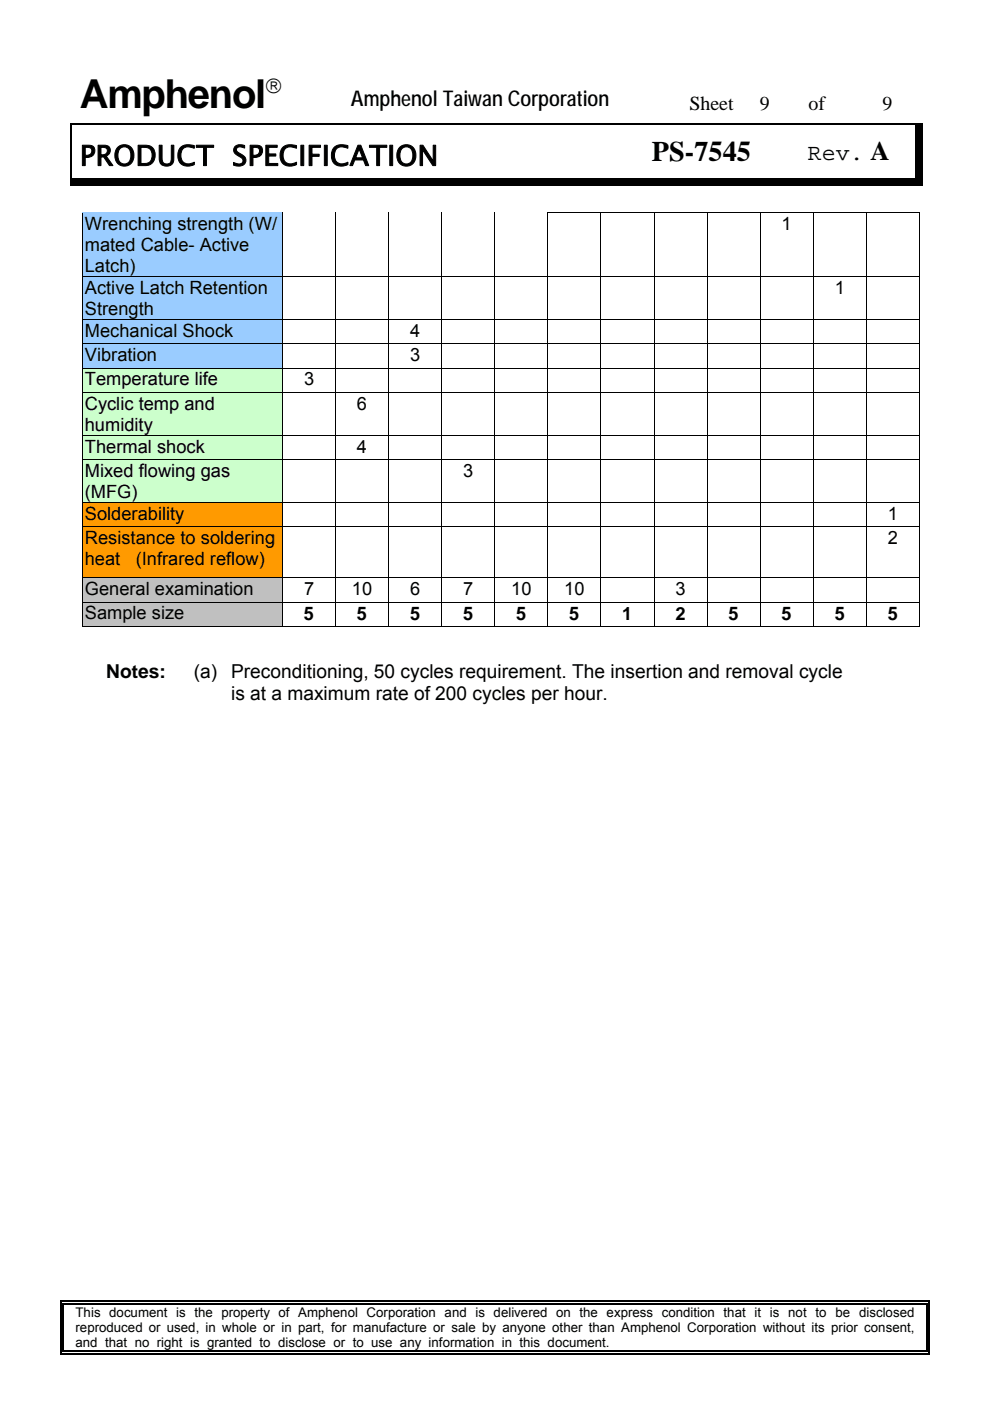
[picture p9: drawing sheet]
<svg xmlns="http://www.w3.org/2000/svg" width="210mm" height="297mm" viewBox="0 0 210 297" stroke-linecap="round" stroke-linejoin="round" font-family="sans-serif">
<defs><g id="words">
<text font-size="8.5" x="16.9" y="22.9">Amphenol</text>
<g font-size="6">
<text x="16.9" y="35.1">PRODUCT SPECIFICATION</text>
<text x="138.3" y="34.1">PS-7545</text>
</g>
<text font-size="5.7" x="184.6" y="33.8">A</text>
<text font-size="4.9" x="171.4" y="33.8">Rev.</text>
<g font-size="4.6">
<text x="56.2" y="19.8">®</text>
<text x="74.4" y="22.4">Amphenol Taiwan Corporation</text>
</g>
<g font-size="4.2">
<text x="146.2" y="23.2">Sheet</text>
<text x="161.2" y="23.2">9</text>
<text x="171.5" y="23.2">of</text>
<text x="187.2" y="23.2">9</text>
</g>
<g font-size="4.1">
<text x="22.5" y="143.8">Notes:</text>
<text x="41.1" y="143.7">(a)</text>
<text x="49" y="143.7">Preconditioning, 50 cycles requirement. The insertion and removal cycle</text>
<text x="49" y="148.5">is at a maximum rate of 200 cycles per hour.</text>
</g>
<g font-size="3.9">
<text x="18" y="48.8">Wrenching strength (W/</text>
<text x="18" y="53.2">mated Cable- Active</text>
<text x="165.8" y="48.8">1</text>
<text x="18" y="57.7">Latch)</text>
<text x="18" y="62.3">Active Latch Retention</text>
<text x="177" y="62.3">1</text>
<text x="18" y="66.7">Strength</text>
<text x="18" y="71.4">Mechanical Shock</text>
<text x="87" y="71.4">4</text>
<text x="18" y="76.5">Vibration</text>
<text x="87" y="76.5">3</text>
<text x="18" y="81.7">Temperature life</text>
<text x="64.5" y="81.7">3</text>
<text x="18" y="86.9">Cyclic temp and</text>
<text x="75.7" y="86.9">6</text>
<text x="18" y="91.4">humidity</text>
<text x="18" y="96">Thermal shock</text>
<text x="75.7" y="96">4</text>
<text x="18" y="101.2">Mixed flowing gas</text>
<text x="98.3" y="101.2">3</text>
<text x="18" y="105.6">(MFG)</text>
<text x="18" y="110.2">Solderability</text>
<text x="188.3" y="110.2">1</text>
<text x="18" y="115.4">Resistance to soldering</text>
<text x="18" y="119.8">heat</text>
<text x="28.8" y="119.8">(Infrared reflow)</text>
<text x="188.3" y="115.4">2</text>
<text x="18" y="126.2">General examination</text>
<text x="18" y="131.3">Sample size</text>
<text x="64.5" y="131.5">5</text>
<text x="64.5" y="126.2">7</text>
<text x="74.6" y="126.2">10</text>
<text x="75.7" y="131.5">5</text>
<text x="87" y="131.5">5</text>
<text x="87" y="126.2">6</text>
<text x="98.3" y="131.5">5</text>
<text x="98.3" y="126.2">7</text>
<text x="108.4" y="126.2">10</text>
<text x="109.5" y="131.5">5</text>
<text x="119.7" y="126.2">10</text>
<text x="120.8" y="131.5">5</text>
<text x="132" y="131.5">1</text>
<text x="143.3" y="126.2">3</text>
<text x="143.3" y="131.5">2</text>
<text x="154.5" y="131.5">5</text>
<text x="165.8" y="131.5">5</text>
<text x="177" y="131.5">5</text>
<text x="188.3" y="131.5">5</text>
</g>
<g font-size="2.8">
<text x="16" y="279.2">This document is the property of Amphenol Corporation and is delivered on the express condition that it is not to be disclosed</text>
<text x="16" y="282.4">reproduced or used, in whole or in part, for manufacture or sale by anyone other than Amphenol Corporation without its prior consent,</text>
<text x="16" y="285.7">and that no right is granted to disclose or to use any information in this document.</text>
</g>
</g></defs>
<g fill="#000">
<path d="M14.9 26.2h.2v.2h-.2zM14.9 37.8h117.6v1.5h-117.6zM132.3 37.8h1.6v1.5h-1.6zM133.9 37.8h31.1v1.5h-31.1zM164.8 37.8h29.4v1.5h-29.4zM194.2 26.2h1.6v.2h-1.6zM194.2 26.4h1.6v12.9h-1.6zM194.2 37.8h1.6v1.5h-1.6zM12.7 275.8h.3v.8h-.3zM12.7 275.8h.8v.2h-.8zM13.2 276.3h.3v.3h-.3zM13.2 276.3h.3v.2h-.3z"/>
<path d="M13.5 275.8h.7v.2h-.7zM13.5 276.3h.7v.2h-.7zM105 275.8h.8v.2h-.8zM105 276.3h.8v.2h-.8zM196.5 275.8h.8v.2h-.8zM196.5 276.3h.3v.3h-.3zM196.5 276.3h.3v.2h-.3zM197 275.8h.3v.8h-.3zM12.7 286.9h.8v.2h-.8zM13.2 286.3h.3v.3h-.3zM196.5 286.9h.8v.2h-.8zM196.5 286.3h.3v.3h-.3z"/>
<path d="M197 286.3h.3v.8h-.3z"/>
</g>
<path d="M14.9 26.3h179.3M15 26.4v11.4M12.8 276.6v10.5M13.4 276.6v9.7M14.2 275.9h90.8M14.2 276.4h90.8M105.8 275.9h90.7M105.8 276.4h90.7M196.6 276.6v9.7M197.1 276.6v9.7M13.5 287h183M13.5 286.5h183" fill="none" stroke="#000" stroke-width=".25"/>
<g fill="#9accff">
<path d="M17.6 45.2h42.2v13.3h-42.2z"/>
<path d="M18 45.2h41.4v4.4h-41.4z"/>
<path d="M18 49.6h41.4v4.5h-41.4z"/>
<path d="M18 54.1h41.4v4.4h-41.4z"/>
</g>
<path d="M17.4 45.1h42.5" fill="none" stroke="#9accff" stroke-width=".21"/>
<path d="M59.9 45h.1v.2h-.1zM71.1 45h.2v.2h-.2zM82.4 45h.1v.2h-.1zM93.6 45h.2v.2h-.2zM104.9 45h.2v.2h-.2zM116.1 45h.2v.2h-.2zM194.9 45h.2v.2h-.2z" fill="#000"/>
<g fill="none" stroke="#000" stroke-width=".21">
<path d="M17.5 45.2v13.3M59.9 45.2v13.3M71.2 45.2v13.3M82.4 45.2v13.3M93.7 45.2v13.3M105 45.2v13.3M116.1 45.1h79M116.2 45.2v13.3M127.5 45.2v13.3M138.7 45.2v13.3M150 45.2v13.3M161.2 45.2v13.3"/>
<path d="M172.5 45.2v13.3M183.8 45.2v13.3M195 45.2v13.3"/>
</g>
<g fill="#9accff">
<path d="M17.6 58.7h42.2v8.9h-42.2z"/>
<path d="M18 58.7h41.4v4.4h-41.4z"/>
<path d="M18 63.1h41.4v4.5h-41.4z"/>
</g>
<g fill="none" stroke="#000" stroke-width=".21">
<path d="M17.4 58.6h177.7M17.5 58.7v8.9M59.9 58.7v8.9M71.2 58.7v8.9M82.4 58.7v8.9M93.7 58.7v8.9M105 58.7v8.9M116.2 58.7v8.9M127.5 58.7v8.9M138.7 58.7v8.9M150 58.7v8.9M161.2 58.7v8.9"/>
<path d="M172.5 58.7v8.9M183.8 58.7v8.9M195 58.7v8.9"/>
</g>
<g fill="#9accff">
<path d="M17.6 67.8h42.2v5h-42.2z"/>
<path d="M18 67.8h41.4v4.4h-41.4z"/>
</g>
<g fill="none" stroke="#000" stroke-width=".21">
<path d="M17.4 67.7h177.7M17.5 67.8v5M59.9 67.8v5M71.2 67.8v5M82.4 67.8v5M93.7 67.8v5M105 67.8v5M116.2 67.8v5M127.5 67.8v5M138.7 67.8v5M150 67.8v5M161.2 67.8v5"/>
<path d="M172.5 67.8v5M183.8 67.8v5M195 67.8v5"/>
</g>
<g fill="#9accff">
<path d="M17.6 72.9h42.2v5.1h-42.2z"/>
<path d="M18 72.9h41.4v4.5h-41.4z"/>
</g>
<g fill="none" stroke="#000" stroke-width=".21">
<path d="M17.4 72.9h177.7M17.5 72.9v5.1M59.9 72.9v5.1M71.2 72.9v5.1M82.4 72.9v5.1M93.7 72.9v5.1M105 72.9v5.1M116.2 72.9v5.1M127.5 72.9v5.1M138.7 72.9v5.1M150 72.9v5.1M161.2 72.9v5.1"/>
<path d="M172.5 72.9v5.1M183.8 72.9v5.1M195 72.9v5.1"/>
</g>
<g fill="#cfc">
<path d="M17.6 78.1h42.2v5h-42.2z"/>
<path d="M18 78.1h41.4v4.5h-41.4z"/>
</g>
<g fill="none" stroke="#000" stroke-width=".21">
<path d="M17.4 78h177.7M17.5 78.1v5M59.9 78.1v5M71.2 78.1v5M82.4 78.1v5M93.7 78.1v5M105 78.1v5M116.2 78.1v5M127.5 78.1v5M138.7 78.1v5M150 78.1v5M161.2 78.1v5"/>
<path d="M172.5 78.1v5M183.8 78.1v5M195 78.1v5"/>
</g>
<g fill="#cfc">
<path d="M17.6 83.3h42.2v8.9h-42.2z"/>
<path d="M18 83.3h41.4v4.5h-41.4z"/>
<path d="M18 87.8h41.4v4.4h-41.4z"/>
</g>
<g fill="none" stroke="#000" stroke-width=".21">
<path d="M17.4 83.2h177.7M17.5 83.3v8.9M59.9 83.3v8.9M71.2 83.3v8.9M82.4 83.3v8.9M93.7 83.3v8.9M105 83.3v8.9M116.2 83.3v8.9M127.5 83.3v8.9M138.7 83.3v8.9M150 83.3v8.9M161.2 83.3v8.9"/>
<path d="M172.5 83.3v8.9M183.8 83.3v8.9M195 83.3v8.9"/>
</g>
<g fill="#cfc">
<path d="M17.6 92.4h42.2v5h-42.2z"/>
<path d="M18 92.4h41.4v4.4h-41.4z"/>
</g>
<g fill="none" stroke="#000" stroke-width=".21">
<path d="M17.4 92.3h177.7M17.5 92.4v5M59.9 92.4v5M71.2 92.4v5M82.4 92.4v5M93.7 92.4v5M105 92.4v5M116.2 92.4v5M127.5 92.4v5M138.7 92.4v5M150 92.4v5M161.2 92.4v5"/>
<path d="M172.5 92.4v5M183.8 92.4v5M195 92.4v5"/>
</g>
<g fill="#cfc">
<path d="M17.6 97.6h42.2v8.8h-42.2z"/>
<path d="M18 97.6h41.4v4.4h-41.4z"/>
<path d="M18 102h41.4v4.4h-41.4z"/>
</g>
<g fill="none" stroke="#000" stroke-width=".21">
<path d="M17.4 97.5h177.7M17.5 97.6v8.8M59.9 97.6v8.8M71.2 97.6v8.8M82.4 97.6v8.8M93.7 97.6v8.8M105 97.6v8.8M116.2 97.6v8.8M127.5 97.6v8.8M138.7 97.6v8.8M150 97.6v8.8M161.2 97.6v8.8"/>
<path d="M172.5 97.6v8.8M183.8 97.6v8.8M195 97.6v8.8"/>
</g>
<g fill="#ff9a00">
<path d="M17.6 106.6h42.2v5h-42.2z"/>
<path d="M18 106.6h41.4v4.5h-41.4z"/>
</g>
<g fill="none" stroke="#000" stroke-width=".21">
<path d="M17.4 106.5h177.7M17.5 106.6v5M59.9 106.6v5M71.2 106.6v5M82.4 106.6v5M93.7 106.6v5M105 106.6v5M116.2 106.6v5M127.5 106.6v5M138.7 106.6v5M150 106.6v5M161.2 106.6v5"/>
<path d="M172.5 106.6v5M183.8 106.6v5M195 106.6v5"/>
</g>
<g fill="#ff9a00">
<path d="M17.6 111.8h42.2v10.6h-42.2z"/>
<path d="M18 111.8h41.4v4.4h-41.4z"/>
<path d="M18 116.2h41.4v4.5h-41.4z"/>
</g>
<g fill="none" stroke="#000" stroke-width=".21">
<path d="M17.4 111.7h177.7M17.5 111.8v10.6M59.9 111.8v10.6M71.2 111.8v10.6M82.4 111.8v10.6M93.7 111.8v10.6M105 111.8v10.6M116.2 111.8v10.6M127.5 111.8v10.6M138.7 111.8v10.6M150 111.8v10.6M161.2 111.8v10.6"/>
<path d="M172.5 111.8v10.6M183.8 111.8v10.6M195 111.8v10.6"/>
</g>
<g fill="#c0c0c0">
<path d="M17.6 122.6h42.2v5h-42.2z"/>
<path d="M18 122.6h41.4v4.4h-41.4z"/>
</g>
<g fill="none" stroke="#000" stroke-width=".21">
<path d="M17.4 122.5h177.7M17.5 122.6v5M59.9 122.6v5M71.2 122.6v5M82.4 122.6v5M93.7 122.6v5M105 122.6v5M116.2 122.6v5M127.5 122.6v5M138.7 122.6v5M150 122.6v5M161.2 122.6v5"/>
<path d="M172.5 122.6v5M183.8 122.6v5M195 122.6v5"/>
</g>
<g fill="#c0c0c0">
<path d="M17.6 127.7h42.2v5.1h-42.2z"/>
<path d="M18 127.7h41.4v4.5h-41.4z"/>
</g>
<g fill="none" stroke="#000" stroke-width=".21">
<path d="M17.4 127.7h177.7M17.4 132.8h42.5M17.5 127.7v5.2M59.9 127.7v5.2M60 132.8h11.1M71.2 127.7v5.2M71.3 132.8h11.1M82.4 127.7v5.2M82.5 132.8h11.1M93.7 127.7v5.2M93.8 132.8h11.1M105 127.7v5.2"/>
<path d="M105.1 132.8h11M116.2 127.7v5.2M116.3 132.8h11.1M127.5 127.7v5.2M127.6 132.8h11M138.7 127.7v5.2M138.8 132.8h11.1M150 127.7v5.2M150.1 132.8h11.1M161.2 127.7v5.2M161.3 132.8h11.1M172.5 127.7v5.2"/>
<path d="M172.6 132.8h11.1M183.8 127.7v5.2M183.9 132.8h11M195 127.7v5.2"/>
</g>
<path d="M194.9 132.8h.2v.1h-.2z" fill="#000"/>
<use href="#words"/>
</svg>
